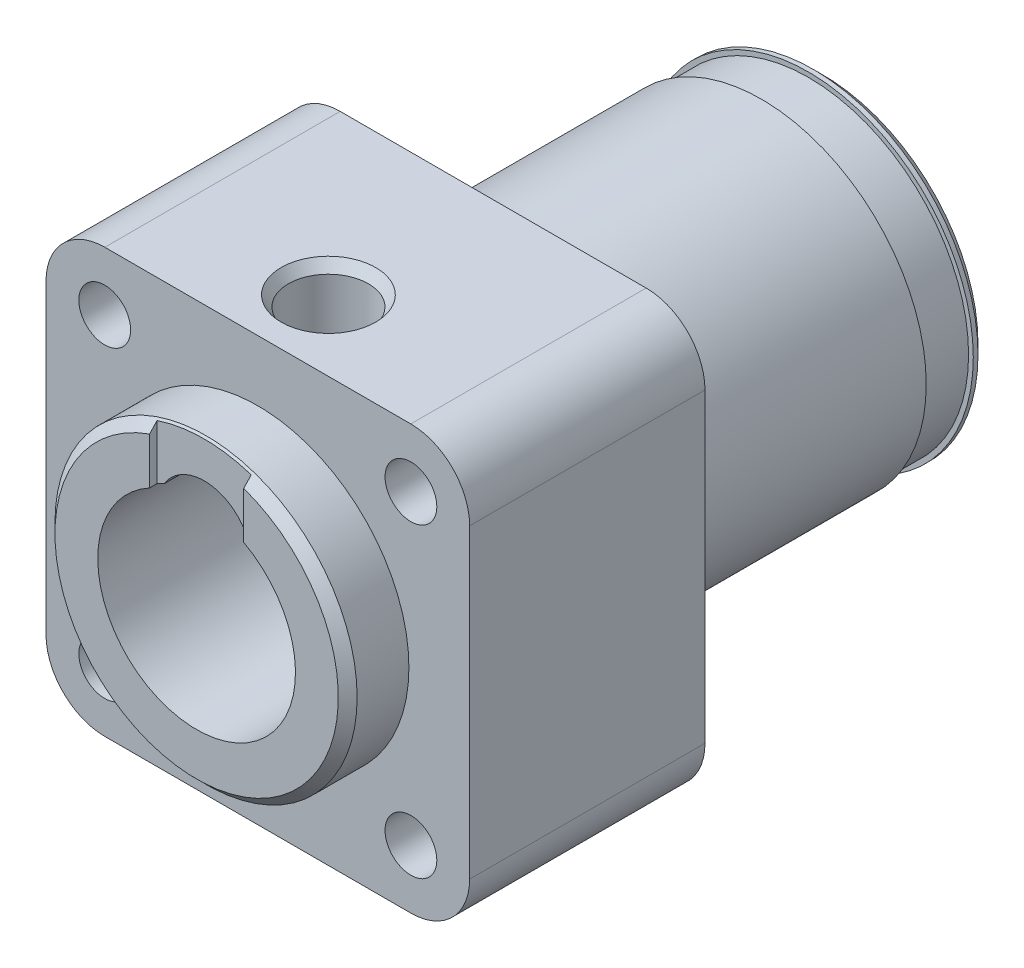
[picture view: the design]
ISO-10303-21;
HEADER;
FILE_DESCRIPTION(('STEP AP214'),'2;1');
FILE_NAME('part.step','',(''),(''),'','','');
FILE_SCHEMA(('AUTOMOTIVE_DESIGN { 1 0 10303 214 1 1 1 1 }'));
ENDSEC;
DATA;
#1=APPLICATION_CONTEXT('core data for automotive mechanical design processes');
#2=APPLICATION_PROTOCOL_DEFINITION('international standard','automotive_design',2000,#1);
#3=PRODUCT_CONTEXT('',#1,'mechanical');
#4=PRODUCT('Part','Part','',(#3));
#5=PRODUCT_RELATED_PRODUCT_CATEGORY('part','',(#4));
#6=PRODUCT_DEFINITION_FORMATION('','',#4);
#7=PRODUCT_DEFINITION_CONTEXT('part definition',#1,'design');
#8=PRODUCT_DEFINITION('design','',#6,#7);
#9=PRODUCT_DEFINITION_SHAPE('','',#8);
#10=(LENGTH_UNIT() NAMED_UNIT(*) SI_UNIT(.MILLI.,.METRE.));
#11=(NAMED_UNIT(*) PLANE_ANGLE_UNIT() SI_UNIT($,.RADIAN.));
#12=(NAMED_UNIT(*) SI_UNIT($,.STERADIAN.) SOLID_ANGLE_UNIT());
#13=UNCERTAINTY_MEASURE_WITH_UNIT(LENGTH_MEASURE(1.E-05),#10,'distance_accuracy_value','');
#14=(GEOMETRIC_REPRESENTATION_CONTEXT(3) GLOBAL_UNCERTAINTY_ASSIGNED_CONTEXT((#13)) GLOBAL_UNIT_ASSIGNED_CONTEXT((#10,
#11,#12)) REPRESENTATION_CONTEXT('',''));
#15=CARTESIAN_POINT('',(0.,0.,0.));
#16=DIRECTION('',(0.,0.,1.));
#17=DIRECTION('',(1.,0.,0.));
#18=AXIS2_PLACEMENT_3D('',#15,#16,#17);
#19=CARTESIAN_POINT('',(0.,23.75,35.));
#20=DIRECTION('',(0.,0.,1.));
#21=DIRECTION('',(1.,0.,0.));
#22=AXIS2_PLACEMENT_3D('',#19,#20,#21);
#23=PLANE('',#22);
#24=CARTESIAN_POINT('',(-16.2634559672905,16.2634559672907,35.));
#25=DIRECTION('',(0.,0.,1.));
#26=DIRECTION('',(1.,0.,0.));
#27=AXIS2_PLACEMENT_3D('',#24,#25,#26);
#28=CIRCLE('',#27,2.74999999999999);
#29=CARTESIAN_POINT('',(-13.5134559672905,16.2634559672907,35.));
#30=VERTEX_POINT('',#29);
#31=EDGE_CURVE('E373',#30,#30,#28,.T.);
#32=ORIENTED_EDGE('',*,*,#31,.T.);
#33=EDGE_LOOP('',(#32));
#34=FACE_BOUND('',#33,.T.);
#35=CARTESIAN_POINT('',(16.2634559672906,16.2634559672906,35.));
#36=DIRECTION('',(0.,0.,1.));
#37=DIRECTION('',(1.,0.,0.));
#38=AXIS2_PLACEMENT_3D('',#35,#36,#37);
#39=CIRCLE('',#38,2.74999999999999);
#40=CARTESIAN_POINT('',(19.0134559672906,16.2634559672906,35.));
#41=VERTEX_POINT('',#40);
#42=EDGE_CURVE('E367',#41,#41,#39,.T.);
#43=ORIENTED_EDGE('',*,*,#42,.T.);
#44=EDGE_LOOP('',(#43));
#45=FACE_BOUND('',#44,.T.);
#46=CARTESIAN_POINT('',(16.2634559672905,-16.2634559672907,35.));
#47=DIRECTION('',(0.,0.,1.));
#48=DIRECTION('',(1.,0.,0.));
#49=AXIS2_PLACEMENT_3D('',#46,#47,#48);
#50=CIRCLE('',#49,2.74999999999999);
#51=CARTESIAN_POINT('',(19.0134559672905,-16.2634559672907,35.));
#52=VERTEX_POINT('',#51);
#53=EDGE_CURVE('E361',#52,#52,#50,.T.);
#54=ORIENTED_EDGE('',*,*,#53,.T.);
#55=EDGE_LOOP('',(#54));
#56=FACE_BOUND('',#55,.T.);
#57=CARTESIAN_POINT('',(-16.2634559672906,-16.2634559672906,35.));
#58=DIRECTION('',(0.,0.,1.));
#59=DIRECTION('',(1.,0.,0.));
#60=AXIS2_PLACEMENT_3D('',#57,#58,#59);
#61=CIRCLE('',#60,2.74999999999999);
#62=CARTESIAN_POINT('',(-13.5134559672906,-16.2634559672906,35.));
#63=VERTEX_POINT('',#62);
#64=EDGE_CURVE('E156',#63,#63,#61,.T.);
#65=ORIENTED_EDGE('',*,*,#64,.T.);
#66=EDGE_LOOP('',(#65));
#67=FACE_BOUND('',#66,.T.);
#68=CARTESIAN_POINT('',(0.,0.,35.));
#69=DIRECTION('',(0.,0.,1.));
#70=DIRECTION('',(1.,0.,0.));
#71=AXIS2_PLACEMENT_3D('',#68,#69,#70);
#72=CIRCLE('',#71,17.5);
#73=CARTESIAN_POINT('',(17.5,0.,35.));
#74=VERTEX_POINT('',#73);
#75=EDGE_CURVE('E241',#74,#74,#72,.T.);
#76=ORIENTED_EDGE('',*,*,#75,.T.);
#77=EDGE_LOOP('',(#76));
#78=FACE_BOUND('',#77,.T.);
#79=CARTESIAN_POINT('',(-16.25,-16.25,35.));
#80=DIRECTION('',(0.,0.,1.));
#81=DIRECTION('',(1.,0.,0.));
#82=AXIS2_PLACEMENT_3D('',#79,#80,#81);
#83=CIRCLE('',#82,6.25);
#84=CARTESIAN_POINT('',(-22.5,-16.25,35.));
#85=VERTEX_POINT('',#84);
#86=CARTESIAN_POINT('',(-16.25,-22.5,35.));
#87=VERTEX_POINT('',#86);
#88=EDGE_CURVE('E270',#85,#87,#83,.T.);
#89=ORIENTED_EDGE('',*,*,#88,.F.);
#90=DIRECTION('',(0.,-1.,0.));
#91=VECTOR('',#90,1.);
#92=CARTESIAN_POINT('',(-22.5,23.75,35.));
#93=LINE('',#92,#91);
#94=CARTESIAN_POINT('',(-22.5,16.25,35.));
#95=VERTEX_POINT('',#94);
#96=EDGE_CURVE('E273',#95,#85,#93,.T.);
#97=ORIENTED_EDGE('',*,*,#96,.F.);
#98=CARTESIAN_POINT('',(-16.25,16.25,35.));
#99=DIRECTION('',(0.,0.,1.));
#100=DIRECTION('',(1.,0.,0.));
#101=AXIS2_PLACEMENT_3D('',#98,#99,#100);
#102=CIRCLE('',#101,6.25);
#103=CARTESIAN_POINT('',(-16.25,22.5,35.));
#104=VERTEX_POINT('',#103);
#105=EDGE_CURVE('E275',#104,#95,#102,.T.);
#106=ORIENTED_EDGE('',*,*,#105,.F.);
#107=DIRECTION('',(-1.,0.,0.));
#108=VECTOR('',#107,1.);
#109=CARTESIAN_POINT('',(0.,22.5,35.));
#110=LINE('',#109,#108);
#111=CARTESIAN_POINT('',(16.25,22.5,35.));
#112=VERTEX_POINT('',#111);
#113=EDGE_CURVE('E277',#112,#104,#110,.T.);
#114=ORIENTED_EDGE('',*,*,#113,.F.);
#115=CARTESIAN_POINT('',(16.25,16.25,35.));
#116=DIRECTION('',(0.,0.,1.));
#117=DIRECTION('',(1.,0.,0.));
#118=AXIS2_PLACEMENT_3D('',#115,#116,#117);
#119=CIRCLE('',#118,6.25);
#120=CARTESIAN_POINT('',(22.5,16.25,35.));
#121=VERTEX_POINT('',#120);
#122=EDGE_CURVE('E279',#121,#112,#119,.T.);
#123=ORIENTED_EDGE('',*,*,#122,.F.);
#124=DIRECTION('',(0.,1.,0.));
#125=VECTOR('',#124,1.);
#126=CARTESIAN_POINT('',(22.5,23.75,35.));
#127=LINE('',#126,#125);
#128=CARTESIAN_POINT('',(22.5,-16.25,35.));
#129=VERTEX_POINT('',#128);
#130=EDGE_CURVE('E281',#129,#121,#127,.T.);
#131=ORIENTED_EDGE('',*,*,#130,.F.);
#132=CARTESIAN_POINT('',(16.25,-16.25,35.));
#133=DIRECTION('',(0.,0.,1.));
#134=DIRECTION('',(1.,0.,0.));
#135=AXIS2_PLACEMENT_3D('',#132,#133,#134);
#136=CIRCLE('',#135,6.25);
#137=CARTESIAN_POINT('',(16.25,-22.5,35.));
#138=VERTEX_POINT('',#137);
#139=EDGE_CURVE('E283',#138,#129,#136,.T.);
#140=ORIENTED_EDGE('',*,*,#139,.F.);
#141=DIRECTION('',(1.,0.,0.));
#142=VECTOR('',#141,1.);
#143=CARTESIAN_POINT('',(0.,-22.5,35.));
#144=LINE('',#143,#142);
#145=EDGE_CURVE('E285',#87,#138,#144,.T.);
#146=ORIENTED_EDGE('',*,*,#145,.F.);
#147=EDGE_LOOP('',(#89,#97,#106,#114,#123,#131,#140,#146));
#148=FACE_BOUND('',#147,.T.);
#149=ADVANCED_FACE('F30',(#34,#45,#56,#67,#78,#148),#23,.F.);
#150=CARTESIAN_POINT('',(0.,0.,60.));
#151=DIRECTION('',(0.,0.,1.));
#152=DIRECTION('',(1.,0.,0.));
#153=AXIS2_PLACEMENT_3D('',#150,#151,#152);
#154=PLANE('',#153);
#155=CARTESIAN_POINT('',(-16.2634559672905,16.2634559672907,60.));
#156=DIRECTION('',(0.,0.,1.));
#157=DIRECTION('',(1.,0.,0.));
#158=AXIS2_PLACEMENT_3D('',#155,#156,#157);
#159=CIRCLE('',#158,2.74999999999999);
#160=CARTESIAN_POINT('',(-13.5134559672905,16.2634559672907,60.));
#161=VERTEX_POINT('',#160);
#162=EDGE_CURVE('E375',#161,#161,#159,.T.);
#163=ORIENTED_EDGE('',*,*,#162,.F.);
#164=EDGE_LOOP('',(#163));
#165=FACE_BOUND('',#164,.T.);
#166=CARTESIAN_POINT('',(16.2634559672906,16.2634559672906,60.));
#167=DIRECTION('',(0.,0.,1.));
#168=DIRECTION('',(1.,0.,0.));
#169=AXIS2_PLACEMENT_3D('',#166,#167,#168);
#170=CIRCLE('',#169,2.74999999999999);
#171=CARTESIAN_POINT('',(19.0134559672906,16.2634559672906,60.));
#172=VERTEX_POINT('',#171);
#173=EDGE_CURVE('E370',#172,#172,#170,.T.);
#174=ORIENTED_EDGE('',*,*,#173,.F.);
#175=EDGE_LOOP('',(#174));
#176=FACE_BOUND('',#175,.T.);
#177=CARTESIAN_POINT('',(16.2634559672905,-16.2634559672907,60.));
#178=DIRECTION('',(0.,0.,1.));
#179=DIRECTION('',(1.,0.,0.));
#180=AXIS2_PLACEMENT_3D('',#177,#178,#179);
#181=CIRCLE('',#180,2.74999999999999);
#182=CARTESIAN_POINT('',(19.0134559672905,-16.2634559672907,60.));
#183=VERTEX_POINT('',#182);
#184=EDGE_CURVE('E364',#183,#183,#181,.T.);
#185=ORIENTED_EDGE('',*,*,#184,.F.);
#186=EDGE_LOOP('',(#185));
#187=FACE_BOUND('',#186,.T.);
#188=CARTESIAN_POINT('',(-16.2634559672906,-16.2634559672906,60.));
#189=DIRECTION('',(0.,0.,1.));
#190=DIRECTION('',(1.,0.,0.));
#191=AXIS2_PLACEMENT_3D('',#188,#189,#190);
#192=CIRCLE('',#191,2.74999999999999);
#193=CARTESIAN_POINT('',(-13.5134559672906,-16.2634559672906,60.));
#194=VERTEX_POINT('',#193);
#195=EDGE_CURVE('E358',#194,#194,#192,.T.);
#196=ORIENTED_EDGE('',*,*,#195,.F.);
#197=EDGE_LOOP('',(#196));
#198=FACE_BOUND('',#197,.T.);
#199=CARTESIAN_POINT('',(0.,0.,60.));
#200=DIRECTION('',(0.,0.,1.));
#201=DIRECTION('',(1.,0.,0.));
#202=AXIS2_PLACEMENT_3D('',#199,#200,#201);
#203=CIRCLE('',#202,16.05);
#204=CARTESIAN_POINT('',(16.05,0.,60.));
#205=VERTEX_POINT('',#204);
#206=EDGE_CURVE('E265',#205,#205,#203,.T.);
#207=ORIENTED_EDGE('',*,*,#206,.F.);
#208=EDGE_LOOP('',(#207));
#209=FACE_BOUND('',#208,.T.);
#210=DIRECTION('',(0.,-1.,0.));
#211=VECTOR('',#210,1.);
#212=CARTESIAN_POINT('',(-22.5,16.25,60.));
#213=LINE('',#212,#211);
#214=CARTESIAN_POINT('',(-22.5,16.25,60.));
#215=VERTEX_POINT('',#214);
#216=CARTESIAN_POINT('',(-22.5,-16.25,60.));
#217=VERTEX_POINT('',#216);
#218=EDGE_CURVE('E291',#215,#217,#213,.T.);
#219=ORIENTED_EDGE('',*,*,#218,.T.);
#220=CARTESIAN_POINT('',(-16.25,-16.25,60.));
#221=DIRECTION('',(0.,0.,1.));
#222=DIRECTION('',(1.,0.,0.));
#223=AXIS2_PLACEMENT_3D('',#220,#221,#222);
#224=CIRCLE('',#223,6.25);
#225=CARTESIAN_POINT('',(-16.25,-22.5,60.));
#226=VERTEX_POINT('',#225);
#227=EDGE_CURVE('E325',#217,#226,#224,.T.);
#228=ORIENTED_EDGE('',*,*,#227,.T.);
#229=DIRECTION('',(1.,0.,0.));
#230=VECTOR('',#229,1.);
#231=CARTESIAN_POINT('',(-16.25,-22.5,60.));
#232=LINE('',#231,#230);
#233=CARTESIAN_POINT('',(16.25,-22.5,60.));
#234=VERTEX_POINT('',#233);
#235=EDGE_CURVE('E322',#226,#234,#232,.T.);
#236=ORIENTED_EDGE('',*,*,#235,.T.);
#237=CARTESIAN_POINT('',(16.25,-16.25,60.));
#238=DIRECTION('',(0.,0.,1.));
#239=DIRECTION('',(1.,0.,0.));
#240=AXIS2_PLACEMENT_3D('',#237,#238,#239);
#241=CIRCLE('',#240,6.25);
#242=CARTESIAN_POINT('',(22.5,-16.25,60.));
#243=VERTEX_POINT('',#242);
#244=EDGE_CURVE('E319',#234,#243,#241,.T.);
#245=ORIENTED_EDGE('',*,*,#244,.T.);
#246=DIRECTION('',(0.,1.,0.));
#247=VECTOR('',#246,1.);
#248=CARTESIAN_POINT('',(22.5,16.25,60.));
#249=LINE('',#248,#247);
#250=CARTESIAN_POINT('',(22.5,16.25,60.));
#251=VERTEX_POINT('',#250);
#252=EDGE_CURVE('E316',#243,#251,#249,.T.);
#253=ORIENTED_EDGE('',*,*,#252,.T.);
#254=CARTESIAN_POINT('',(16.25,16.25,60.));
#255=DIRECTION('',(0.,0.,1.));
#256=DIRECTION('',(1.,0.,0.));
#257=AXIS2_PLACEMENT_3D('',#254,#255,#256);
#258=CIRCLE('',#257,6.25);
#259=CARTESIAN_POINT('',(16.25,22.5,60.));
#260=VERTEX_POINT('',#259);
#261=EDGE_CURVE('E313',#251,#260,#258,.T.);
#262=ORIENTED_EDGE('',*,*,#261,.T.);
#263=DIRECTION('',(-1.,0.,0.));
#264=VECTOR('',#263,1.);
#265=CARTESIAN_POINT('',(-16.25,22.5,60.));
#266=LINE('',#265,#264);
#267=CARTESIAN_POINT('',(-16.25,22.5,60.));
#268=VERTEX_POINT('',#267);
#269=EDGE_CURVE('E310',#260,#268,#266,.T.);
#270=ORIENTED_EDGE('',*,*,#269,.T.);
#271=CARTESIAN_POINT('',(-16.25,16.25,60.));
#272=DIRECTION('',(0.,0.,1.));
#273=DIRECTION('',(1.,0.,0.));
#274=AXIS2_PLACEMENT_3D('',#271,#272,#273);
#275=CIRCLE('',#274,6.25);
#276=EDGE_CURVE('E307',#268,#215,#275,.T.);
#277=ORIENTED_EDGE('',*,*,#276,.T.);
#278=EDGE_LOOP('',(#219,#228,#236,#245,#253,#262,#270,#277));
#279=FACE_BOUND('',#278,.T.);
#280=ADVANCED_FACE('F201',(#165,#176,#187,#198,#209,#279),#154,.T.);
#281=CARTESIAN_POINT('',(0.,0.,66.5));
#282=DIRECTION('',(0.,0.,1.));
#283=DIRECTION('',(1.,0.,0.));
#284=AXIS2_PLACEMENT_3D('',#281,#282,#283);
#285=PLANE('',#284);
#286=DIRECTION('',(0.,-1.,0.));
#287=VECTOR('',#286,1.);
#288=CARTESIAN_POINT('',(-5.,0.,66.5));
#289=LINE('',#288,#287);
#290=CARTESIAN_POINT('',(-5.,14.1951576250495,66.5));
#291=VERTEX_POINT('',#290);
#292=CARTESIAN_POINT('',(-5.,9.23309265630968,66.5));
#293=VERTEX_POINT('',#292);
#294=EDGE_CURVE('E141',#291,#293,#289,.T.);
#295=ORIENTED_EDGE('',*,*,#294,.F.);
#296=CARTESIAN_POINT('',(0.,0.,66.5));
#297=DIRECTION('',(0.,0.,1.));
#298=DIRECTION('',(1.,0.,0.));
#299=AXIS2_PLACEMENT_3D('',#296,#297,#298);
#300=CIRCLE('',#299,15.05);
#301=CARTESIAN_POINT('',(5.,14.1951576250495,66.5));
#302=VERTEX_POINT('',#301);
#303=EDGE_CURVE('E152',#291,#302,#300,.T.);
#304=ORIENTED_EDGE('',*,*,#303,.T.);
#305=DIRECTION('',(0.,1.,0.));
#306=VECTOR('',#305,1.);
#307=CARTESIAN_POINT('',(5.,0.,66.5));
#308=LINE('',#307,#306);
#309=CARTESIAN_POINT('',(5.,9.23309265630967,66.5));
#310=VERTEX_POINT('',#309);
#311=EDGE_CURVE('E155',#310,#302,#308,.T.);
#312=ORIENTED_EDGE('',*,*,#311,.F.);
#313=CARTESIAN_POINT('',(0.,0.,66.5));
#314=DIRECTION('',(0.,0.,-1.));
#315=DIRECTION('',(-1.,0.,0.));
#316=AXIS2_PLACEMENT_3D('',#313,#314,#315);
#317=CIRCLE('',#316,10.5);
#318=EDGE_CURVE('E154',#310,#293,#317,.T.);
#319=ORIENTED_EDGE('',*,*,#318,.T.);
#320=EDGE_LOOP('',(#295,#304,#312,#319));
#321=FACE_BOUND('',#320,.T.);
#322=ADVANCED_FACE('F150',(#321),#285,.T.);
#323=CARTESIAN_POINT('',(0.,0.,0.));
#324=DIRECTION('',(0.,0.,-1.));
#325=DIRECTION('',(-1.,0.,0.));
#326=AXIS2_PLACEMENT_3D('',#323,#324,#325);
#327=CYLINDRICAL_SURFACE('',#326,10.5);
#328=ORIENTED_EDGE('',*,*,#318,.F.);
#329=DIRECTION('',(0.,0.,-1.));
#330=VECTOR('',#329,1.);
#331=CARTESIAN_POINT('',(5.,9.23309265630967,0.));
#332=LINE('',#331,#330);
#333=CARTESIAN_POINT('',(5.,9.23309265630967,65.7));
#334=VERTEX_POINT('',#333);
#335=EDGE_CURVE('E344',#310,#334,#332,.T.);
#336=ORIENTED_EDGE('',*,*,#335,.T.);
#337=CARTESIAN_POINT('',(0.,0.,65.7));
#338=DIRECTION('',(0.,0.,-1.));
#339=DIRECTION('',(-1.,0.,0.));
#340=AXIS2_PLACEMENT_3D('',#337,#338,#339);
#341=CIRCLE('',#340,10.5);
#342=CARTESIAN_POINT('',(4.30463640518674,9.57706141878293,65.7));
#343=VERTEX_POINT('',#342);
#344=EDGE_CURVE('E349',#334,#343,#341,.F.);
#345=ORIENTED_EDGE('',*,*,#344,.T.);
#346=DIRECTION('',(0.,0.,1.));
#347=VECTOR('',#346,1.);
#348=CARTESIAN_POINT('',(4.30463640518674,9.57706141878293,46.5));
#349=LINE('',#348,#347);
#350=CARTESIAN_POINT('',(4.30463640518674,9.57706141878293,46.5));
#351=VERTEX_POINT('',#350);
#352=EDGE_CURVE('E334',#351,#343,#349,.T.);
#353=ORIENTED_EDGE('',*,*,#352,.F.);
#354=CARTESIAN_POINT('',(0.,0.,46.5));
#355=DIRECTION('',(0.,0.,-1.));
#356=DIRECTION('',(-1.,0.,0.));
#357=AXIS2_PLACEMENT_3D('',#354,#355,#356);
#358=CIRCLE('',#357,10.5);
#359=CARTESIAN_POINT('',(-4.24999999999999,9.60143218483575,46.5));
#360=VERTEX_POINT('',#359);
#361=EDGE_CURVE('E177',#351,#360,#358,.F.);
#362=ORIENTED_EDGE('',*,*,#361,.T.);
#363=DIRECTION('',(0.,0.,1.));
#364=VECTOR('',#363,1.);
#365=CARTESIAN_POINT('',(-4.24999999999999,9.60143218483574,46.5));
#366=LINE('',#365,#364);
#367=CARTESIAN_POINT('',(-4.24999999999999,9.60143218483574,52.5));
#368=VERTEX_POINT('',#367);
#369=EDGE_CURVE('E335',#360,#368,#366,.T.);
#370=ORIENTED_EDGE('',*,*,#369,.T.);
#371=CARTESIAN_POINT('',(-4.24999999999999,9.60143218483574,65.7));
#372=VERTEX_POINT('',#371);
#373=EDGE_CURVE('E338',#368,#372,#366,.T.);
#374=ORIENTED_EDGE('',*,*,#373,.T.);
#375=CARTESIAN_POINT('',(-5.,9.23309265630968,65.7));
#376=VERTEX_POINT('',#375);
#377=EDGE_CURVE('E50',#372,#376,#341,.F.);
#378=ORIENTED_EDGE('',*,*,#377,.T.);
#379=DIRECTION('',(0.,0.,-1.));
#380=VECTOR('',#379,1.);
#381=CARTESIAN_POINT('',(-5.,9.23309265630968,0.));
#382=LINE('',#381,#380);
#383=EDGE_CURVE('E342',#376,#293,#382,.F.);
#384=ORIENTED_EDGE('',*,*,#383,.T.);
#385=EDGE_LOOP('',(#328,#336,#345,#353,#362,#370,#374,#378,#384));
#386=FACE_BOUND('',#385,.T.);
#387=CARTESIAN_POINT('',(0.,0.,32.));
#388=DIRECTION('',(0.,0.,-1.));
#389=DIRECTION('',(-1.,0.,0.));
#390=AXIS2_PLACEMENT_3D('',#387,#388,#389);
#391=CIRCLE('',#390,10.5);
#392=CARTESIAN_POINT('',(-10.5,0.,32.));
#393=VERTEX_POINT('',#392);
#394=EDGE_CURVE('E246',#393,#393,#391,.F.);
#395=ORIENTED_EDGE('',*,*,#394,.F.);
#396=EDGE_LOOP('',(#395));
#397=FACE_BOUND('',#396,.T.);
#398=ADVANCED_FACE('F217',(#386,#397),#327,.F.);
#399=CARTESIAN_POINT('',(0.,0.,66.5));
#400=DIRECTION('',(0.,0.,1.));
#401=DIRECTION('',(1.,0.,0.));
#402=AXIS2_PLACEMENT_3D('',#399,#400,#401);
#403=CYLINDRICAL_SURFACE('',#402,17.5);
#404=ORIENTED_EDGE('',*,*,#75,.F.);
#405=EDGE_LOOP('',(#404));
#406=FACE_BOUND('',#405,.T.);
#407=CARTESIAN_POINT('',(0.,0.,6.50000000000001));
#408=DIRECTION('',(0.,0.,1.));
#409=DIRECTION('',(1.,0.,0.));
#410=AXIS2_PLACEMENT_3D('',#407,#408,#409);
#411=CIRCLE('',#410,17.5);
#412=CARTESIAN_POINT('',(17.5,0.,6.50000000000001));
#413=VERTEX_POINT('',#412);
#414=EDGE_CURVE('E243',#413,#413,#411,.T.);
#415=ORIENTED_EDGE('',*,*,#414,.T.);
#416=EDGE_LOOP('',(#415));
#417=FACE_BOUND('',#416,.T.);
#418=ADVANCED_FACE('F452',(#406,#417),#403,.T.);
#419=CARTESIAN_POINT('',(0.,23.75,6.5));
#420=DIRECTION('',(0.,0.,-1.));
#421=DIRECTION('',(-1.,0.,0.));
#422=AXIS2_PLACEMENT_3D('',#419,#420,#421);
#423=PLANE('',#422);
#424=CARTESIAN_POINT('',(0.,0.,6.5));
#425=DIRECTION('',(0.,0.,1.));
#426=DIRECTION('',(1.,0.,0.));
#427=AXIS2_PLACEMENT_3D('',#424,#425,#426);
#428=CIRCLE('',#427,17.);
#429=CARTESIAN_POINT('',(17.,0.,6.5));
#430=VERTEX_POINT('',#429);
#431=EDGE_CURVE('E252',#430,#430,#428,.T.);
#432=ORIENTED_EDGE('',*,*,#431,.T.);
#433=EDGE_LOOP('',(#432));
#434=FACE_BOUND('',#433,.T.);
#435=ORIENTED_EDGE('',*,*,#414,.F.);
#436=EDGE_LOOP('',(#435));
#437=FACE_BOUND('',#436,.T.);
#438=ADVANCED_FACE('F213',(#434,#437),#423,.T.);
#439=CARTESIAN_POINT('',(0.,0.,66.5));
#440=DIRECTION('',(0.,0.,1.));
#441=DIRECTION('',(1.,0.,0.));
#442=AXIS2_PLACEMENT_3D('',#439,#440,#441);
#443=CYLINDRICAL_SURFACE('',#442,17.);
#444=CARTESIAN_POINT('',(0.,0.,1.5));
#445=DIRECTION('',(0.,0.,1.));
#446=DIRECTION('',(1.,0.,0.));
#447=AXIS2_PLACEMENT_3D('',#444,#445,#446);
#448=CIRCLE('',#447,17.);
#449=CARTESIAN_POINT('',(17.,0.,1.5));
#450=VERTEX_POINT('',#449);
#451=EDGE_CURVE('E255',#450,#450,#448,.T.);
#452=ORIENTED_EDGE('',*,*,#451,.T.);
#453=EDGE_LOOP('',(#452));
#454=FACE_BOUND('',#453,.T.);
#455=ORIENTED_EDGE('',*,*,#431,.F.);
#456=EDGE_LOOP('',(#455));
#457=FACE_BOUND('',#456,.T.);
#458=ADVANCED_FACE('F458',(#454,#457),#443,.T.);
#459=CARTESIAN_POINT('',(0.,23.75,1.5));
#460=DIRECTION('',(0.,0.,1.));
#461=DIRECTION('',(1.,0.,0.));
#462=AXIS2_PLACEMENT_3D('',#459,#460,#461);
#463=PLANE('',#462);
#464=CARTESIAN_POINT('',(0.,0.,1.5));
#465=DIRECTION('',(0.,0.,1.));
#466=DIRECTION('',(1.,0.,0.));
#467=AXIS2_PLACEMENT_3D('',#464,#465,#466);
#468=CIRCLE('',#467,17.5);
#469=CARTESIAN_POINT('',(17.5,0.,1.5));
#470=VERTEX_POINT('',#469);
#471=EDGE_CURVE('E258',#470,#470,#468,.T.);
#472=ORIENTED_EDGE('',*,*,#471,.T.);
#473=EDGE_LOOP('',(#472));
#474=FACE_BOUND('',#473,.T.);
#475=ORIENTED_EDGE('',*,*,#451,.F.);
#476=EDGE_LOOP('',(#475));
#477=FACE_BOUND('',#476,.T.);
#478=ADVANCED_FACE('F456',(#474,#477),#463,.T.);
#479=CARTESIAN_POINT('',(0.,0.,1.00000000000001));
#480=DIRECTION('',(0.,0.,1.));
#481=DIRECTION('',(1.,0.,0.));
#482=AXIS2_PLACEMENT_3D('',#479,#480,#481);
#483=CIRCLE('',#482,17.5);
#484=CARTESIAN_POINT('',(17.5,0.,1.00000000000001));
#485=VERTEX_POINT('',#484);
#486=EDGE_CURVE('E167',#485,#485,#483,.T.);
#487=ORIENTED_EDGE('',*,*,#486,.T.);
#488=EDGE_LOOP('',(#487));
#489=FACE_BOUND('',#488,.T.);
#490=ORIENTED_EDGE('',*,*,#471,.F.);
#491=EDGE_LOOP('',(#490));
#492=FACE_BOUND('',#491,.T.);
#493=ADVANCED_FACE('F221',(#489,#492),#403,.T.);
#494=CARTESIAN_POINT('',(0.,0.,0.));
#495=DIRECTION('',(0.,0.,1.));
#496=DIRECTION('',(1.,0.,0.));
#497=AXIS2_PLACEMENT_3D('',#494,#495,#496);
#498=PLANE('',#497);
#499=CARTESIAN_POINT('',(0.,0.,0.));
#500=DIRECTION('',(0.,0.,1.));
#501=DIRECTION('',(1.,0.,0.));
#502=AXIS2_PLACEMENT_3D('',#499,#500,#501);
#503=CIRCLE('',#502,16.5);
#504=CARTESIAN_POINT('',(16.5,0.,0.));
#505=VERTEX_POINT('',#504);
#506=EDGE_CURVE('E161',#505,#505,#503,.F.);
#507=ORIENTED_EDGE('',*,*,#506,.T.);
#508=EDGE_LOOP('',(#507));
#509=FACE_BOUND('',#508,.T.);
#510=CARTESIAN_POINT('',(0.,0.,0.));
#511=DIRECTION('',(0.,0.,-1.));
#512=DIRECTION('',(-1.,0.,0.));
#513=AXIS2_PLACEMENT_3D('',#510,#511,#512);
#514=CIRCLE('',#513,14.5);
#515=CARTESIAN_POINT('',(-14.5,0.,0.));
#516=VERTEX_POINT('',#515);
#517=EDGE_CURVE('E262',#516,#516,#514,.T.);
#518=ORIENTED_EDGE('',*,*,#517,.F.);
#519=EDGE_LOOP('',(#518));
#520=FACE_BOUND('',#519,.T.);
#521=ADVANCED_FACE('F218',(#509,#520),#498,.F.);
#522=CARTESIAN_POINT('',(0.,0.,32.));
#523=DIRECTION('',(0.,0.,-1.));
#524=DIRECTION('',(-1.,0.,0.));
#525=AXIS2_PLACEMENT_3D('',#522,#523,#524);
#526=PLANE('',#525);
#527=CARTESIAN_POINT('',(0.,0.,32.));
#528=DIRECTION('',(0.,0.,-1.));
#529=DIRECTION('',(-1.,0.,0.));
#530=AXIS2_PLACEMENT_3D('',#527,#528,#529);
#531=CIRCLE('',#530,14.5);
#532=CARTESIAN_POINT('',(-14.5,0.,32.));
#533=VERTEX_POINT('',#532);
#534=EDGE_CURVE('E248',#533,#533,#531,.T.);
#535=ORIENTED_EDGE('',*,*,#534,.T.);
#536=EDGE_LOOP('',(#535));
#537=FACE_BOUND('',#536,.T.);
#538=ORIENTED_EDGE('',*,*,#394,.T.);
#539=EDGE_LOOP('',(#538));
#540=FACE_BOUND('',#539,.T.);
#541=ADVANCED_FACE('F220',(#537,#540),#526,.T.);
#542=CARTESIAN_POINT('',(0.,0.,32.));
#543=DIRECTION('',(0.,0.,-1.));
#544=DIRECTION('',(-1.,0.,0.));
#545=AXIS2_PLACEMENT_3D('',#542,#543,#544);
#546=CYLINDRICAL_SURFACE('',#545,14.5);
#547=ORIENTED_EDGE('',*,*,#534,.F.);
#548=EDGE_LOOP('',(#547));
#549=FACE_BOUND('',#548,.T.);
#550=ORIENTED_EDGE('',*,*,#517,.T.);
#551=EDGE_LOOP('',(#550));
#552=FACE_BOUND('',#551,.T.);
#553=ADVANCED_FACE('F226',(#549,#552),#546,.F.);
#554=CARTESIAN_POINT('',(0.,0.,1.00000000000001));
#555=DIRECTION('',(0.,0.,1.));
#556=DIRECTION('',(1.,0.,0.));
#557=AXIS2_PLACEMENT_3D('',#554,#555,#556);
#558=CONICAL_SURFACE('',#557,17.5,0.785398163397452);
#559=ORIENTED_EDGE('',*,*,#506,.F.);
#560=EDGE_LOOP('',(#559));
#561=FACE_BOUND('',#560,.T.);
#562=ORIENTED_EDGE('',*,*,#486,.F.);
#563=EDGE_LOOP('',(#562));
#564=FACE_BOUND('',#563,.T.);
#565=ADVANCED_FACE('F223',(#561,#564),#558,.T.);
#566=CARTESIAN_POINT('',(0.,0.,60.));
#567=DIRECTION('',(0.,0.,1.));
#568=DIRECTION('',(1.,0.,0.));
#569=AXIS2_PLACEMENT_3D('',#566,#567,#568);
#570=CYLINDRICAL_SURFACE('',#569,16.05);
#571=CARTESIAN_POINT('',(0.,0.,65.5));
#572=DIRECTION('',(0.,0.,1.));
#573=DIRECTION('',(1.,0.,0.));
#574=AXIS2_PLACEMENT_3D('',#571,#572,#573);
#575=CIRCLE('',#574,16.05);
#576=CARTESIAN_POINT('',(16.05,0.,65.5));
#577=VERTEX_POINT('',#576);
#578=EDGE_CURVE('E160',#577,#577,#575,.F.);
#579=CARTESIAN_POINT('',(16.05,0.,65.5));
#580=CARTESIAN_POINT('',(16.05,0.,65.4427083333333));
#581=CARTESIAN_POINT('',(16.05,0.,65.3854166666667));
#582=CARTESIAN_POINT('',(16.05,0.,65.2708333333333));
#583=CARTESIAN_POINT('',(16.05,0.,65.2135416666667));
#584=CARTESIAN_POINT('',(16.05,0.,65.0989583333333));
#585=CARTESIAN_POINT('',(16.05,0.,65.0416666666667));
#586=CARTESIAN_POINT('',(16.05,0.,64.9270833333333));
#587=CARTESIAN_POINT('',(16.05,0.,64.8697916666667));
#588=CARTESIAN_POINT('',(16.05,0.,64.7552083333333));
#589=CARTESIAN_POINT('',(16.05,0.,64.6979166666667));
#590=CARTESIAN_POINT('',(16.05,0.,64.5833333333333));
#591=CARTESIAN_POINT('',(16.05,0.,64.5260416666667));
#592=CARTESIAN_POINT('',(16.05,0.,64.4114583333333));
#593=CARTESIAN_POINT('',(16.05,0.,64.3541666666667));
#594=CARTESIAN_POINT('',(16.05,0.,64.2395833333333));
#595=CARTESIAN_POINT('',(16.05,0.,64.1822916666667));
#596=CARTESIAN_POINT('',(16.05,0.,64.0677083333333));
#597=CARTESIAN_POINT('',(16.05,0.,64.0104166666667));
#598=CARTESIAN_POINT('',(16.05,0.,63.8958333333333));
#599=CARTESIAN_POINT('',(16.05,0.,63.8385416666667));
#600=CARTESIAN_POINT('',(16.05,0.,63.7239583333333));
#601=CARTESIAN_POINT('',(16.05,0.,63.6666666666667));
#602=CARTESIAN_POINT('',(16.05,0.,63.5520833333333));
#603=CARTESIAN_POINT('',(16.05,0.,63.4947916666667));
#604=CARTESIAN_POINT('',(16.05,0.,63.3802083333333));
#605=CARTESIAN_POINT('',(16.05,0.,63.3229166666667));
#606=CARTESIAN_POINT('',(16.05,0.,63.2083333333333));
#607=CARTESIAN_POINT('',(16.05,0.,63.1510416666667));
#608=CARTESIAN_POINT('',(16.05,0.,63.0364583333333));
#609=CARTESIAN_POINT('',(16.05,0.,62.9791666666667));
#610=CARTESIAN_POINT('',(16.05,0.,62.8645833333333));
#611=CARTESIAN_POINT('',(16.05,0.,62.8072916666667));
#612=CARTESIAN_POINT('',(16.05,0.,62.6927083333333));
#613=CARTESIAN_POINT('',(16.05,0.,62.6354166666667));
#614=CARTESIAN_POINT('',(16.05,0.,62.5208333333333));
#615=CARTESIAN_POINT('',(16.05,0.,62.4635416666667));
#616=CARTESIAN_POINT('',(16.05,0.,62.3489583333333));
#617=CARTESIAN_POINT('',(16.05,0.,62.2916666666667));
#618=CARTESIAN_POINT('',(16.05,0.,62.1770833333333));
#619=CARTESIAN_POINT('',(16.05,0.,62.1197916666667));
#620=CARTESIAN_POINT('',(16.05,0.,62.0052083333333));
#621=CARTESIAN_POINT('',(16.05,0.,61.9479166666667));
#622=CARTESIAN_POINT('',(16.05,0.,61.8333333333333));
#623=CARTESIAN_POINT('',(16.05,0.,61.7760416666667));
#624=CARTESIAN_POINT('',(16.05,0.,61.6614583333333));
#625=CARTESIAN_POINT('',(16.05,0.,61.6041666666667));
#626=CARTESIAN_POINT('',(16.05,0.,61.4895833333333));
#627=CARTESIAN_POINT('',(16.05,0.,61.4322916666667));
#628=CARTESIAN_POINT('',(16.05,0.,61.3177083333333));
#629=CARTESIAN_POINT('',(16.05,0.,61.2604166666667));
#630=CARTESIAN_POINT('',(16.05,0.,61.1458333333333));
#631=CARTESIAN_POINT('',(16.05,0.,61.0885416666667));
#632=CARTESIAN_POINT('',(16.05,0.,60.9739583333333));
#633=CARTESIAN_POINT('',(16.05,0.,60.9166666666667));
#634=CARTESIAN_POINT('',(16.05,0.,60.8020833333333));
#635=CARTESIAN_POINT('',(16.05,0.,60.7447916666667));
#636=CARTESIAN_POINT('',(16.05,0.,60.6302083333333));
#637=CARTESIAN_POINT('',(16.05,0.,60.5729166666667));
#638=CARTESIAN_POINT('',(16.05,0.,60.4583333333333));
#639=CARTESIAN_POINT('',(16.05,0.,60.4010416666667));
#640=CARTESIAN_POINT('',(16.05,0.,60.2864583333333));
#641=CARTESIAN_POINT('',(16.05,0.,60.2291666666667));
#642=CARTESIAN_POINT('',(16.05,0.,60.1145833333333));
#643=CARTESIAN_POINT('',(16.05,0.,60.0572916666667));
#644=CARTESIAN_POINT('',(16.05,0.,60.));
#645=B_SPLINE_CURVE_WITH_KNOTS('',3,(#579,#580,#581,#582,#583,#584,#585,#586,#587,#588,#589,
#590,#591,#592,#593,#594,#595,#596,#597,#598,#599,#600,#601,#602,#603,#604,#605,#606,#607,#608,
#609,#610,#611,#612,#613,#614,#615,#616,#617,#618,#619,#620,#621,#622,#623,#624,#625,#626,#627,
#628,#629,#630,#631,#632,#633,#634,#635,#636,#637,#638,#639,#640,#641,#642,#643,#644),
.UNSPECIFIED.,.F.,.F.,(4,2,2,2,2,2,2,2,2,2,2,2,2,2,2,2,2,2,2,2,2,2,2,2,2,2,2,2,2,2,2,2,4),(0.,
0.171874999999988,0.34374999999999,0.515624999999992,0.687499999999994,0.859374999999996,
1.03125,1.203125,1.37499999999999,1.54687499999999,1.71874999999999,1.89062499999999,
2.06249999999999,2.234375,2.40624999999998,2.57812499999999,2.74999999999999,2.92187499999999,
3.09374999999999,3.26562499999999,3.43749999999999,3.60937499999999,3.78124999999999,
3.95312499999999,4.12499999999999,4.29687499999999,4.46874999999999,4.64062499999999,
4.81249999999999,4.98437499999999,5.15624999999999,5.32812499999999,5.49999999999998),.UNSPECIFIED.);
#646=EDGE_CURVE('BSEAM225',#577,#205,#645,.T.);
#647=ORIENTED_EDGE('',*,*,#578,.T.);
#648=ORIENTED_EDGE('',*,*,#206,.T.);
#649=ORIENTED_EDGE('',*,*,#646,.T.);
#650=ORIENTED_EDGE('',*,*,#646,.F.);
#651=EDGE_LOOP('',(#647,#649,#648,#650));
#652=FACE_BOUND('',#651,.T.);
#653=ADVANCED_FACE('F225',(#652),#570,.T.);
#654=CARTESIAN_POINT('',(0.,0.,66.5));
#655=DIRECTION('',(0.,0.,-1.));
#656=DIRECTION('',(-1.,0.,0.));
#657=AXIS2_PLACEMENT_3D('',#654,#655,#656);
#658=CONICAL_SURFACE('',#657,15.05,0.785398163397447);
#659=CARTESIAN_POINT('',(-5.,27.070309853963,54.0218021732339));
#660=CARTESIAN_POINT('',(-5.,26.5424236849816,54.5408982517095));
#661=CARTESIAN_POINT('',(-5.,26.0142960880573,55.0597491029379));
#662=CARTESIAN_POINT('',(-5.,24.9574402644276,56.0968402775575));
#663=CARTESIAN_POINT('',(-5.,24.4287120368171,56.6150806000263));
#664=CARTESIAN_POINT('',(-5.,23.3705205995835,57.6508468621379));
#665=CARTESIAN_POINT('',(-5.,22.8410573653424,58.1683727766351));
#666=CARTESIAN_POINT('',(-5.,21.7812543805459,59.2025259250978));
#667=CARTESIAN_POINT('',(-5.,21.2509146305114,59.7191531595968));
#668=CARTESIAN_POINT('',(-5.,20.1893306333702,60.7511162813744));
#669=CARTESIAN_POINT('',(-5.,19.6580867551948,61.2664525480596));
#670=CARTESIAN_POINT('',(-5.,18.594235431,62.2957155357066));
#671=CARTESIAN_POINT('',(-5.,18.0616279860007,62.8096422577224));
#672=CARTESIAN_POINT('',(-5.,16.9946664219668,63.8356765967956));
#673=CARTESIAN_POINT('',(-5.,16.4603123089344,64.3477842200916));
#674=CARTESIAN_POINT('',(-5.,15.3893173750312,65.3696018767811));
#675=CARTESIAN_POINT('',(-5.,14.852676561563,65.8793119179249));
#676=CARTESIAN_POINT('',(-5.,13.8464597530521,66.8292438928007));
#677=CARTESIAN_POINT('',(-5.,13.3772594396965,67.2698635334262));
#678=CARTESIAN_POINT('',(-5.,12.4357769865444,68.1477801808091));
#679=CARTESIAN_POINT('',(-5.,11.9634949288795,68.5850772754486));
#680=CARTESIAN_POINT('',(-5.,11.2518562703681,69.2375924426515));
#681=CARTESIAN_POINT('',(-5.,11.0140883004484,69.4545429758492));
#682=CARTESIAN_POINT('',(-5.,10.5372900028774,69.887049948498));
#683=CARTESIAN_POINT('',(-5.,10.2982596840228,70.1026063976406));
#684=CARTESIAN_POINT('',(-5.,9.81867664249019,70.5320619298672));
#685=CARTESIAN_POINT('',(-5.,9.57812379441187,70.7459608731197));
#686=CARTESIAN_POINT('',(-5.,9.0951786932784,71.1716826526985));
#687=CARTESIAN_POINT('',(-5.,8.85278639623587,71.3835054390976));
#688=CARTESIAN_POINT('',(-5.,8.60931175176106,71.5940847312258));
#689=B_SPLINE_CURVE_WITH_KNOTS('',3,(#659,#660,#661,#662,#663,#664,#665,#666,#667,#668,#669,
#670,#671,#672,#673,#674,#675,#676,#677,#678,#679,#680,#681,#682,#683,#684,#685,#686,#687,#688),
.UNSPECIFIED.,.F.,.F.,(4,2,2,2,2,2,2,2,2,2,2,2,2,2,4),(0.,2.22106323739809,4.44212982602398,
6.66327269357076,8.88441424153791,11.1048004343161,13.3251849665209,15.5455618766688,
17.7659316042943,19.6968928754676,21.6278028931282,22.5934124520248,23.5590152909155,
24.5246987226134,25.4904053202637),.UNSPECIFIED.);
#690=CARTESIAN_POINT('',(-5.,15.0406947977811,65.7));
#691=VERTEX_POINT('',#690);
#692=EDGE_CURVE('E11',#691,#291,#689,.T.);
#693=ORIENTED_EDGE('',*,*,#692,.F.);
#694=CARTESIAN_POINT('',(0.,0.,65.7));
#695=DIRECTION('',(0.,0.,-1.));
#696=DIRECTION('',(-1.,0.,0.));
#697=AXIS2_PLACEMENT_3D('',#694,#695,#696);
#698=CIRCLE('',#697,15.85);
#699=CARTESIAN_POINT('',(5.,15.0406947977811,65.7));
#700=VERTEX_POINT('',#699);
#701=EDGE_CURVE('E347',#700,#691,#698,.F.);
#702=ORIENTED_EDGE('',*,*,#701,.F.);
#703=CARTESIAN_POINT('',(5.,8.60931175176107,71.5940847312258));
#704=CARTESIAN_POINT('',(5.,8.85278639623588,71.3835054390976));
#705=CARTESIAN_POINT('',(5.,9.09517869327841,71.1716826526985));
#706=CARTESIAN_POINT('',(5.,9.57812379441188,70.7459608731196));
#707=CARTESIAN_POINT('',(5.,9.8186766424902,70.5320619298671));
#708=CARTESIAN_POINT('',(5.,10.2982596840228,70.1026063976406));
#709=CARTESIAN_POINT('',(5.,10.5372900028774,69.887049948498));
#710=CARTESIAN_POINT('',(5.,11.0140883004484,69.4545429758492));
#711=CARTESIAN_POINT('',(5.,11.2518562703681,69.2375924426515));
#712=CARTESIAN_POINT('',(5.,11.9634949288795,68.5850772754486));
#713=CARTESIAN_POINT('',(5.,12.4357769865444,68.1477801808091));
#714=CARTESIAN_POINT('',(5.,13.3772594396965,67.2698635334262));
#715=CARTESIAN_POINT('',(5.,13.8464597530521,66.8292438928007));
#716=CARTESIAN_POINT('',(5.,14.852676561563,65.8793119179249));
#717=CARTESIAN_POINT('',(5.,15.3893173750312,65.3696018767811));
#718=CARTESIAN_POINT('',(5.,16.4603123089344,64.3477842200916));
#719=CARTESIAN_POINT('',(5.,16.9946664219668,63.8356765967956));
#720=CARTESIAN_POINT('',(5.,18.0616279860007,62.8096422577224));
#721=CARTESIAN_POINT('',(5.,18.594235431,62.2957155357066));
#722=CARTESIAN_POINT('',(5.,19.6580867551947,61.2664525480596));
#723=CARTESIAN_POINT('',(5.,20.1893306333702,60.7511162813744));
#724=CARTESIAN_POINT('',(5.,21.2509146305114,59.7191531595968));
#725=CARTESIAN_POINT('',(5.,21.7812543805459,59.2025259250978));
#726=CARTESIAN_POINT('',(5.,22.8410573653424,58.1683727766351));
#727=CARTESIAN_POINT('',(5.,23.3705205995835,57.6508468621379));
#728=CARTESIAN_POINT('',(5.,24.4287120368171,56.6150806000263));
#729=CARTESIAN_POINT('',(5.,24.9574402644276,56.0968402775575));
#730=CARTESIAN_POINT('',(5.,26.0142960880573,55.0597491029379));
#731=CARTESIAN_POINT('',(5.,26.5424236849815,54.5408982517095));
#732=CARTESIAN_POINT('',(5.,27.070309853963,54.0218021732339));
#733=B_SPLINE_CURVE_WITH_KNOTS('',3,(#703,#704,#705,#706,#707,#708,#709,#710,#711,#712,#713,
#714,#715,#716,#717,#718,#719,#720,#721,#722,#723,#724,#725,#726,#727,#728,#729,#730,#731,#732),
.UNSPECIFIED.,.F.,.F.,(4,2,2,2,2,2,2,2,2,2,2,2,2,2,4),(0.,0.96570659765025,1.93139002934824,
2.89699286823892,3.86260242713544,5.79351244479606,7.72447371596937,9.94484344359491,
12.1652203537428,14.3856048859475,16.6059910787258,18.8271326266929,21.0482754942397,
23.2693420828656,25.4904053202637),.UNSPECIFIED.);
#734=EDGE_CURVE('E43',#302,#700,#733,.T.);
#735=ORIENTED_EDGE('',*,*,#734,.F.);
#736=ORIENTED_EDGE('',*,*,#303,.F.);
#737=EDGE_LOOP('',(#693,#702,#735,#736));
#738=FACE_BOUND('',#737,.T.);
#739=ORIENTED_EDGE('',*,*,#578,.F.);
#740=EDGE_LOOP('',(#739));
#741=FACE_BOUND('',#740,.T.);
#742=ADVANCED_FACE('F32',(#738,#741),#658,.T.);
#743=CARTESIAN_POINT('',(-16.25,-16.25,31.5));
#744=DIRECTION('',(0.,0.,1.));
#745=DIRECTION('',(1.,0.,0.));
#746=AXIS2_PLACEMENT_3D('',#743,#744,#745);
#747=CYLINDRICAL_SURFACE('',#746,6.25);
#748=ORIENTED_EDGE('',*,*,#88,.T.);
#749=DIRECTION('',(0.,0.,1.));
#750=VECTOR('',#749,1.);
#751=CARTESIAN_POINT('',(-16.25,-22.5,31.5));
#752=LINE('',#751,#750);
#753=EDGE_CURVE('E288',#87,#226,#752,.T.);
#754=ORIENTED_EDGE('',*,*,#753,.T.);
#755=ORIENTED_EDGE('',*,*,#227,.F.);
#756=DIRECTION('',(0.,0.,1.));
#757=VECTOR('',#756,1.);
#758=CARTESIAN_POINT('',(-22.5,-16.25,31.5));
#759=LINE('',#758,#757);
#760=EDGE_CURVE('E287',#85,#217,#759,.T.);
#761=ORIENTED_EDGE('',*,*,#760,.F.);
#762=EDGE_LOOP('',(#748,#754,#755,#761));
#763=FACE_BOUND('',#762,.T.);
#764=ADVANCED_FACE('F400',(#763),#747,.T.);
#765=CARTESIAN_POINT('',(-22.5,16.25,31.5));
#766=DIRECTION('',(-1.,0.,0.));
#767=DIRECTION('',(0.,-1.,0.));
#768=AXIS2_PLACEMENT_3D('',#765,#766,#767);
#769=PLANE('',#768);
#770=ORIENTED_EDGE('',*,*,#96,.T.);
#771=ORIENTED_EDGE('',*,*,#760,.T.);
#772=ORIENTED_EDGE('',*,*,#218,.F.);
#773=DIRECTION('',(0.,0.,1.));
#774=VECTOR('',#773,1.);
#775=CARTESIAN_POINT('',(-22.5,16.25,31.5));
#776=LINE('',#775,#774);
#777=EDGE_CURVE('E302',#95,#215,#776,.T.);
#778=ORIENTED_EDGE('',*,*,#777,.F.);
#779=EDGE_LOOP('',(#770,#771,#772,#778));
#780=FACE_BOUND('',#779,.T.);
#781=ADVANCED_FACE('F395',(#780),#769,.T.);
#782=CARTESIAN_POINT('',(-16.25,16.25,31.5));
#783=DIRECTION('',(0.,0.,1.));
#784=DIRECTION('',(1.,0.,0.));
#785=AXIS2_PLACEMENT_3D('',#782,#783,#784);
#786=CYLINDRICAL_SURFACE('',#785,6.25);
#787=ORIENTED_EDGE('',*,*,#105,.T.);
#788=ORIENTED_EDGE('',*,*,#777,.T.);
#789=ORIENTED_EDGE('',*,*,#276,.F.);
#790=DIRECTION('',(0.,0.,1.));
#791=VECTOR('',#790,1.);
#792=CARTESIAN_POINT('',(-16.25,22.5,31.5));
#793=LINE('',#792,#791);
#794=EDGE_CURVE('E300',#104,#268,#793,.T.);
#795=ORIENTED_EDGE('',*,*,#794,.F.);
#796=EDGE_LOOP('',(#787,#788,#789,#795));
#797=FACE_BOUND('',#796,.T.);
#798=ADVANCED_FACE('F426',(#797),#786,.T.);
#799=CARTESIAN_POINT('',(-16.25,22.5,31.5));
#800=DIRECTION('',(0.,1.,0.));
#801=DIRECTION('',(0.,0.,1.));
#802=AXIS2_PLACEMENT_3D('',#799,#800,#801);
#803=PLANE('',#802);
#804=CARTESIAN_POINT('',(0.,22.5,52.5));
#805=DIRECTION('',(0.,1.,0.));
#806=DIRECTION('',(0.,0.,1.));
#807=AXIS2_PLACEMENT_3D('',#804,#805,#806);
#808=CIRCLE('',#807,5.025);
#809=CARTESIAN_POINT('',(0.,22.5,57.525));
#810=VERTEX_POINT('',#809);
#811=EDGE_CURVE('E331',#810,#810,#808,.T.);
#812=ORIENTED_EDGE('',*,*,#811,.F.);
#813=EDGE_LOOP('',(#812));
#814=FACE_BOUND('',#813,.T.);
#815=ORIENTED_EDGE('',*,*,#113,.T.);
#816=ORIENTED_EDGE('',*,*,#794,.T.);
#817=ORIENTED_EDGE('',*,*,#269,.F.);
#818=DIRECTION('',(0.,0.,1.));
#819=VECTOR('',#818,1.);
#820=CARTESIAN_POINT('',(16.25,22.5,31.5));
#821=LINE('',#820,#819);
#822=EDGE_CURVE('E298',#112,#260,#821,.T.);
#823=ORIENTED_EDGE('',*,*,#822,.F.);
#824=EDGE_LOOP('',(#815,#816,#817,#823));
#825=FACE_BOUND('',#824,.T.);
#826=ADVANCED_FACE('F421',(#814,#825),#803,.T.);
#827=CARTESIAN_POINT('',(16.25,16.25,31.5));
#828=DIRECTION('',(0.,0.,1.));
#829=DIRECTION('',(1.,0.,0.));
#830=AXIS2_PLACEMENT_3D('',#827,#828,#829);
#831=CYLINDRICAL_SURFACE('',#830,6.25);
#832=ORIENTED_EDGE('',*,*,#122,.T.);
#833=ORIENTED_EDGE('',*,*,#822,.T.);
#834=ORIENTED_EDGE('',*,*,#261,.F.);
#835=DIRECTION('',(0.,0.,1.));
#836=VECTOR('',#835,1.);
#837=CARTESIAN_POINT('',(22.5,16.25,31.5));
#838=LINE('',#837,#836);
#839=EDGE_CURVE('E296',#121,#251,#838,.T.);
#840=ORIENTED_EDGE('',*,*,#839,.F.);
#841=EDGE_LOOP('',(#832,#833,#834,#840));
#842=FACE_BOUND('',#841,.T.);
#843=ADVANCED_FACE('F417',(#842),#831,.T.);
#844=CARTESIAN_POINT('',(22.5,16.25,31.5));
#845=DIRECTION('',(1.,0.,0.));
#846=DIRECTION('',(0.,1.,0.));
#847=AXIS2_PLACEMENT_3D('',#844,#845,#846);
#848=PLANE('',#847);
#849=ORIENTED_EDGE('',*,*,#130,.T.);
#850=ORIENTED_EDGE('',*,*,#839,.T.);
#851=ORIENTED_EDGE('',*,*,#252,.F.);
#852=DIRECTION('',(0.,0.,1.));
#853=VECTOR('',#852,1.);
#854=CARTESIAN_POINT('',(22.5,-16.25,31.5));
#855=LINE('',#854,#853);
#856=EDGE_CURVE('E294',#129,#243,#855,.T.);
#857=ORIENTED_EDGE('',*,*,#856,.F.);
#858=EDGE_LOOP('',(#849,#850,#851,#857));
#859=FACE_BOUND('',#858,.T.);
#860=ADVANCED_FACE('F412',(#859),#848,.T.);
#861=CARTESIAN_POINT('',(16.25,-16.25,31.5));
#862=DIRECTION('',(0.,0.,1.));
#863=DIRECTION('',(1.,0.,0.));
#864=AXIS2_PLACEMENT_3D('',#861,#862,#863);
#865=CYLINDRICAL_SURFACE('',#864,6.25);
#866=ORIENTED_EDGE('',*,*,#139,.T.);
#867=ORIENTED_EDGE('',*,*,#856,.T.);
#868=ORIENTED_EDGE('',*,*,#244,.F.);
#869=DIRECTION('',(0.,0.,1.));
#870=VECTOR('',#869,1.);
#871=CARTESIAN_POINT('',(16.25,-22.5,31.5));
#872=LINE('',#871,#870);
#873=EDGE_CURVE('E290',#138,#234,#872,.T.);
#874=ORIENTED_EDGE('',*,*,#873,.F.);
#875=EDGE_LOOP('',(#866,#867,#868,#874));
#876=FACE_BOUND('',#875,.T.);
#877=ADVANCED_FACE('F407',(#876),#865,.T.);
#878=CARTESIAN_POINT('',(-16.25,-22.5,31.5));
#879=DIRECTION('',(0.,-1.,0.));
#880=DIRECTION('',(0.,0.,-1.));
#881=AXIS2_PLACEMENT_3D('',#878,#879,#880);
#882=PLANE('',#881);
#883=ORIENTED_EDGE('',*,*,#145,.T.);
#884=ORIENTED_EDGE('',*,*,#873,.T.);
#885=ORIENTED_EDGE('',*,*,#235,.F.);
#886=ORIENTED_EDGE('',*,*,#753,.F.);
#887=EDGE_LOOP('',(#883,#884,#885,#886));
#888=FACE_BOUND('',#887,.T.);
#889=ADVANCED_FACE('F196',(#888),#882,.T.);
#890=CARTESIAN_POINT('',(0.,22.5,52.5));
#891=DIRECTION('',(0.,1.,0.));
#892=DIRECTION('',(0.,0.,1.));
#893=AXIS2_PLACEMENT_3D('',#890,#891,#892);
#894=CYLINDRICAL_SURFACE('',#893,4.24999999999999);
#895=CARTESIAN_POINT('',(0.,11.9999318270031,56.75));
#896=CARTESIAN_POINT('',(-0.100444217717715,11.9995326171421,56.7500014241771));
#897=CARTESIAN_POINT('',(-0.200861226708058,11.9960986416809,56.7464341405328));
#898=CARTESIAN_POINT('',(-0.400843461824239,11.9832415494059,56.7322421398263));
#899=CARTESIAN_POINT('',(-0.500408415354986,11.9738165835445,56.7216152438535));
#900=CARTESIAN_POINT('',(-0.69792587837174,11.9491713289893,56.6934899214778));
#901=CARTESIAN_POINT('',(-0.795876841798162,11.9339457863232,56.6759852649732));
#902=CARTESIAN_POINT('',(-0.989374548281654,11.8980308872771,56.6344225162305));
#903=CARTESIAN_POINT('',(-1.08492017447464,11.877339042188,56.6103614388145));
#904=CARTESIAN_POINT('',(-1.36567981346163,11.8079800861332,56.5292812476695));
#905=CARTESIAN_POINT('',(-1.54651798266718,11.7518328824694,56.4631428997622));
#906=CARTESIAN_POINT('',(-1.89272829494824,11.6233786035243,56.309989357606));
#907=CARTESIAN_POINT('',(-2.05809687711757,11.5510678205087,56.222969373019));
#908=CARTESIAN_POINT('',(-2.32318880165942,11.4186134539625,56.0610935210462));
#909=CARTESIAN_POINT('',(-2.4273774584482,11.3616407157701,55.990821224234));
#910=CARTESIAN_POINT('',(-2.62751427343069,11.2431420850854,55.842777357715));
#911=CARTESIAN_POINT('',(-2.72346213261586,11.1816160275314,55.7650055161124));
#912=CARTESIAN_POINT('',(-2.90728046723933,11.0550740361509,55.6024694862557));
#913=CARTESIAN_POINT('',(-2.99512899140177,10.9900493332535,55.5176874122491));
#914=CARTESIAN_POINT('',(-3.16248351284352,10.8578899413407,55.341818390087));
#915=CARTESIAN_POINT('',(-3.24199061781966,10.7907555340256,55.2507322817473));
#916=CARTESIAN_POINT('',(-3.39422070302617,10.6543042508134,55.0606428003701));
#917=CARTESIAN_POINT('',(-3.46677630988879,10.5849705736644,54.9615175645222));
#918=CARTESIAN_POINT('',(-3.60327223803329,10.4469613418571,54.7570005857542));
#919=CARTESIAN_POINT('',(-3.66720961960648,10.3782860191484,54.6516067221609));
#920=CARTESIAN_POINT('',(-3.78616584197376,10.2436711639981,54.4346133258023));
#921=CARTESIAN_POINT('',(-3.84120435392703,10.1777258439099,54.3230282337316));
#922=CARTESIAN_POINT('',(-3.94212196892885,10.0509722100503,54.0930852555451));
#923=CARTESIAN_POINT('',(-3.98800879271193,9.99015959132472,53.9747331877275));
#924=CARTESIAN_POINT('',(-4.07213639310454,9.87404370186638,53.7241755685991));
#925=CARTESIAN_POINT('',(-4.10984130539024,9.8192049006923,53.5915680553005));
#926=CARTESIAN_POINT('',(-4.17283290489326,9.72465675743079,53.3182247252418));
#927=CARTESIAN_POINT('',(-4.19814640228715,9.6849147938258,53.177507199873));
#928=CARTESIAN_POINT('',(-4.22559170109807,9.64113449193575,52.9607716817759));
#929=CARTESIAN_POINT('',(-4.23300129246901,9.62915030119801,52.8869892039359));
#930=CARTESIAN_POINT('',(-4.24395964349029,9.61134246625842,52.7384173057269));
#931=CARTESIAN_POINT('',(-4.24751053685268,9.60551541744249,52.6636284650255));
#932=CARTESIAN_POINT('',(-4.2506380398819,9.60038659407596,52.5137715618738));
#933=CARTESIAN_POINT('',(-4.25021632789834,9.60108206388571,52.438703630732));
#934=CARTESIAN_POINT('',(-4.24542271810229,9.60893347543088,52.2890516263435));
#935=CARTESIAN_POINT('',(-4.24105083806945,9.61608938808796,52.2144675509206));
#936=CARTESIAN_POINT('',(-4.22406026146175,9.64362135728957,52.01443923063));
#937=CARTESIAN_POINT('',(-4.20780596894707,9.66975271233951,51.8900672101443));
#938=CARTESIAN_POINT('',(-4.16532671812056,9.73585024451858,51.6468370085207));
#939=CARTESIAN_POINT('',(-4.13908553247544,9.77583892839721,51.5279881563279));
#940=CARTESIAN_POINT('',(-4.08028174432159,9.86190476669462,51.3058872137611));
#941=CARTESIAN_POINT('',(-4.04840313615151,9.90722663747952,51.2021514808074));
#942=CARTESIAN_POINT('',(-3.9778268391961,10.0035381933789,50.9997004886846));
#943=CARTESIAN_POINT('',(-3.9391238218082,10.0545322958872,50.9009892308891));
#944=CARTESIAN_POINT('',(-3.8552312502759,10.1602886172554,50.7081363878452));
#945=CARTESIAN_POINT('',(-3.81002601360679,10.2150597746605,50.6140066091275));
#946=CARTESIAN_POINT('',(-3.71345266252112,10.3267143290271,50.4303305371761));
#947=CARTESIAN_POINT('',(-3.66208607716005,10.3835971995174,50.3407831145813));
#948=CARTESIAN_POINT('',(-3.54905525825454,10.5027583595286,50.1592719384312));
#949=CARTESIAN_POINT('',(-3.48690077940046,10.5651121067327,50.0676622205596));
#950=CARTESIAN_POINT('',(-3.35559328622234,10.6896831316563,49.8894938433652));
#951=CARTESIAN_POINT('',(-3.28643809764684,10.7519003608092,49.8029367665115));
#952=CARTESIAN_POINT('',(-3.06863215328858,10.9365740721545,49.5512362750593));
#953=CARTESIAN_POINT('',(-2.9094128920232,11.0573017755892,49.3936965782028));
#954=CARTESIAN_POINT('',(-2.57467589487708,11.2784628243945,49.1120742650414));
#955=CARTESIAN_POINT('',(-2.40101001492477,11.3797186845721,48.9864427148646));
#956=CARTESIAN_POINT('',(-2.02992084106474,11.5651570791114,48.7598098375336));
#957=CARTESIAN_POINT('',(-1.83252075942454,11.6493560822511,48.6587847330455));
#958=CARTESIAN_POINT('',(-1.45259496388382,11.7816950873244,48.5016040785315));
#959=CARTESIAN_POINT('',(-1.27333043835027,11.8335435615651,48.440723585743));
#960=CARTESIAN_POINT('',(-0.903947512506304,11.9175121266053,48.342862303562));
#961=CARTESIAN_POINT('',(-0.713837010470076,11.9496463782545,48.3058643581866));
#962=CARTESIAN_POINT('',(-0.327034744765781,11.9917236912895,48.2581065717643));
#963=CARTESIAN_POINT('',(-0.130318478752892,12.0015720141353,48.2474587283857));
#964=CARTESIAN_POINT('',(0.262476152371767,11.9979454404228,48.2535687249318));
#965=CARTESIAN_POINT('',(0.458554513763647,11.9844704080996,48.2703267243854));
#966=CARTESIAN_POINT('',(0.830669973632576,11.9371313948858,48.3280029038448));
#967=CARTESIAN_POINT('',(1.00716578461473,11.904707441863,48.3672110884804));
#968=CARTESIAN_POINT('',(1.35011809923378,11.823013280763,48.466197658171));
#969=CARTESIAN_POINT('',(1.51657311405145,11.7737405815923,48.5259790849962));
#970=CARTESIAN_POINT('',(1.85065721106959,11.6564190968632,48.6694074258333));
#971=CARTESIAN_POINT('',(2.01714081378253,11.5871142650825,48.754672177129));
#972=CARTESIAN_POINT('',(2.33349382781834,11.4359894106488,48.9431378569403));
#973=CARTESIAN_POINT('',(2.48334870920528,11.3541585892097,49.0463542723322));
#974=CARTESIAN_POINT('',(2.72988773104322,11.2037144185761,49.2399116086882));
#975=CARTESIAN_POINT('',(2.83042746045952,11.1370006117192,49.3268953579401));
#976=CARTESIAN_POINT('',(3.0218249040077,11.000286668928,49.5085979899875));
#977=CARTESIAN_POINT('',(3.11268213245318,10.9302863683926,49.6033172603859));
#978=CARTESIAN_POINT('',(3.28489061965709,10.7884512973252,49.8001603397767));
#979=CARTESIAN_POINT('',(3.36622283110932,10.7166131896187,49.9022983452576));
#980=CARTESIAN_POINT('',(3.51916686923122,10.5729833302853,50.1135860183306));
#981=CARTESIAN_POINT('',(3.59078214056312,10.5011915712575,50.2227331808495));
#982=CARTESIAN_POINT('',(3.70674780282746,10.3782290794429,50.4186852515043));
#983=CARTESIAN_POINT('',(3.75333156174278,10.3265738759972,50.5038717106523));
#984=CARTESIAN_POINT('',(3.84100957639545,10.2254812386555,50.678277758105));
#985=CARTESIAN_POINT('',(3.88210514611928,10.1760432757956,50.7674963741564));
#986=CARTESIAN_POINT('',(3.95850327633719,10.0807914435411,50.9499954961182));
#987=CARTESIAN_POINT('',(3.99381824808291,10.0349699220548,51.04326674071));
#988=CARTESIAN_POINT('',(4.05836787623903,9.94853471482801,51.2341795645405));
#989=CARTESIAN_POINT('',(4.0876057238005,9.90791830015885,51.3318188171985));
#990=CARTESIAN_POINT('',(4.1473180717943,9.82277525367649,51.5617645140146));
#991=CARTESIAN_POINT('',(4.17550756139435,9.78076190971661,51.6956473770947));
#992=CARTESIAN_POINT('',(4.21904577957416,9.71458777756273,51.9696336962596));
#993=CARTESIAN_POINT('',(4.23442647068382,9.69038256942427,52.1097207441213));
#994=CARTESIAN_POINT('',(4.2510811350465,9.66413205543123,52.3941330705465));
#995=CARTESIAN_POINT('',(4.2522356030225,9.66227448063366,52.5384840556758));
#996=CARTESIAN_POINT('',(4.23998670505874,9.68163442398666,52.8250547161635));
#997=CARTESIAN_POINT('',(4.22656490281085,9.70288116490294,52.9672714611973));
#998=CARTESIAN_POINT('',(4.18185160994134,9.7713384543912,53.2775615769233));
#999=CARTESIAN_POINT('',(4.14714745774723,9.82341422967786,53.4440157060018));
#1000=CARTESIAN_POINT('',(4.06065147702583,9.94585804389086,53.7655176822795));
#1001=CARTESIAN_POINT('',(4.00880088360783,10.0162888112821,53.9205240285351));
#1002=CARTESIAN_POINT('',(3.9012360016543,10.153013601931,54.1911070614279));
#1003=CARTESIAN_POINT('',(3.84808577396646,10.2175911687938,54.3086138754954));
#1004=CARTESIAN_POINT('',(3.7323546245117,10.3504569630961,54.5367630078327));
#1005=CARTESIAN_POINT('',(3.66976830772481,10.4187472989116,54.6474013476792));
#1006=CARTESIAN_POINT('',(3.53535771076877,10.5568177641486,54.8621617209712));
#1007=CARTESIAN_POINT('',(3.46352187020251,10.6265996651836,54.9662753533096));
#1008=CARTESIAN_POINT('',(3.31075537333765,10.7657681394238,55.1678426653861));
#1009=CARTESIAN_POINT('',(3.22982664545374,10.8351547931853,55.2652977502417));
#1010=CARTESIAN_POINT('',(3.05589588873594,10.9743664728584,55.4565648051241));
#1011=CARTESIAN_POINT('',(2.96257419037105,11.0441243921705,55.5501359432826));
#1012=CARTESIAN_POINT('',(2.76612125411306,11.1800159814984,55.7293583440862));
#1013=CARTESIAN_POINT('',(2.66298806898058,11.2461489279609,55.8150080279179));
#1014=CARTESIAN_POINT('',(2.44725167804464,11.3730452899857,55.9773001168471));
#1015=CARTESIAN_POINT('',(2.3346734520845,11.4338220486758,56.0539650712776));
#1016=CARTESIAN_POINT('',(2.10021887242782,11.5485427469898,56.1973610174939));
#1017=CARTESIAN_POINT('',(1.97834812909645,11.6024907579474,56.2640979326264));
#1018=CARTESIAN_POINT('',(1.68249145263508,11.7189738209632,56.4073094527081));
#1019=CARTESIAN_POINT('',(1.5049166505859,11.7781537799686,56.4793315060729));
#1020=CARTESIAN_POINT('',(1.2291816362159,11.8524798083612,56.5695196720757));
#1021=CARTESIAN_POINT('',(1.13575539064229,11.8748404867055,56.5965994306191));
#1022=CARTESIAN_POINT('',(0.946235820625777,11.9143721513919,56.6444752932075));
#1023=CARTESIAN_POINT('',(0.850143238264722,11.9315445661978,56.6652731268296));
#1024=CARTESIAN_POINT('',(0.629754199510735,11.9642085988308,56.7049482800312));
#1025=CARTESIAN_POINT('',(0.504831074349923,11.978002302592,56.7218002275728));
#1026=CARTESIAN_POINT('',(0.253257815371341,11.9961165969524,56.7443264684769));
#1027=CARTESIAN_POINT('',(0.12660729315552,12.0004350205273,56.7499982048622));
#1028=CARTESIAN_POINT('',(0.,11.9999318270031,56.75));
#1029=B_SPLINE_CURVE_WITH_KNOTS('',3,(#895,#896,#897,#898,#899,#900,#901,#902,#903,#904,#905,
#906,#907,#908,#909,#910,#911,#912,#913,#914,#915,#916,#917,#918,#919,#920,#921,#922,#923,#924,
#925,#926,#927,#928,#929,#930,#931,#932,#933,#934,#935,#936,#937,#938,#939,#940,#941,#942,#943,
#944,#945,#946,#947,#948,#949,#950,#951,#952,#953,#954,#955,#956,#957,#958,#959,#960,#961,#962,
#963,#964,#965,#966,#967,#968,#969,#970,#971,#972,#973,#974,#975,#976,#977,#978,#979,#980,#981,
#982,#983,#984,#985,#986,#987,#988,#989,#990,#991,#992,#993,#994,#995,#996,#997,#998,#999,#1000,
#1001,#1002,#1003,#1004,#1005,#1006,#1007,#1008,#1009,#1010,#1011,#1012,#1013,#1014,#1015,#1016,
#1017,#1018,#1019,#1020,#1021,#1022,#1023,#1024,#1025,#1026,#1027,#1028),.UNSPECIFIED.,.T.,.F.,
(4,2,2,2,2,2,2,2,2,2,2,2,2,2,2,2,2,2,2,2,2,2,2,2,2,2,2,2,2,2,2,2,2,2,2,2,2,2,2,2,2,2,2,2,2,2,2,
2,2,2,2,2,2,2,2,2,2,2,2,2,2,2,2,2,2,2,4),(0.,0.301200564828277,0.602494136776,0.904061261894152,
1.20576592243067,1.80464492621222,2.40366144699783,2.8171000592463,3.23055366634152,
3.64509678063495,4.05958477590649,4.48235787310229,4.90527481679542,5.32724371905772,
5.74885511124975,6.19287010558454,6.63592013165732,6.86095929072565,7.08587394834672,
7.31069358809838,7.53551221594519,7.9182400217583,8.30159238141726,8.65390077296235,
9.00648548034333,9.35993529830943,9.7132975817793,10.0941517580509,10.4751245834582,
11.2355857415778,11.944188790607,12.6521043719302,13.2385299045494,13.8245337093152,
14.4130240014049,15.0015177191,15.5502250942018,16.0990136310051,16.695303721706,
17.292110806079,17.7378060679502,18.1835236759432,18.6301178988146,19.0765533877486,
19.4062817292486,19.7359309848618,20.0648629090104,20.3936216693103,20.8215027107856,
21.2483128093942,21.6787058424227,22.1096438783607,22.6401642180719,23.1725219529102,
23.6046807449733,24.0370875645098,24.470040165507,24.9029011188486,25.3506601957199,
25.798508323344,26.2452072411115,26.6916385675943,27.2904634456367,27.5895859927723,
27.888626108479,28.2681946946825,28.6478500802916),.UNSPECIFIED.);
#1030=EDGE_CURVE('E164',#368,#368,#1029,.T.);
#1031=ORIENTED_EDGE('',*,*,#1030,.T.);
#1032=EDGE_LOOP('',(#1031));
#1033=FACE_BOUND('',#1032,.T.);
#1034=CARTESIAN_POINT('',(0.,21.3931852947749,52.5));
#1035=DIRECTION('',(0.,1.,0.));
#1036=DIRECTION('',(0.,0.,1.));
#1037=AXIS2_PLACEMENT_3D('',#1034,#1035,#1036);
#1038=CIRCLE('',#1037,4.25);
#1039=CARTESIAN_POINT('',(0.,21.3931852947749,56.75));
#1040=VERTEX_POINT('',#1039);
#1041=EDGE_CURVE('E328',#1040,#1040,#1038,.T.);
#1042=ORIENTED_EDGE('',*,*,#1041,.T.);
#1043=EDGE_LOOP('',(#1042));
#1044=FACE_BOUND('',#1043,.T.);
#1045=ADVANCED_FACE('F179',(#1033,#1044),#894,.F.);
#1046=CARTESIAN_POINT('',(0.,22.5,52.5));
#1047=DIRECTION('',(0.,1.,0.));
#1048=DIRECTION('',(0.,0.,1.));
#1049=AXIS2_PLACEMENT_3D('',#1046,#1047,#1048);
#1050=CONICAL_SURFACE('',#1049,5.025,0.610865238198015);
#1051=ORIENTED_EDGE('',*,*,#1041,.F.);
#1052=EDGE_LOOP('',(#1051));
#1053=FACE_BOUND('',#1052,.T.);
#1054=ORIENTED_EDGE('',*,*,#811,.T.);
#1055=EDGE_LOOP('',(#1054));
#1056=FACE_BOUND('',#1055,.T.);
#1057=ADVANCED_FACE('F189',(#1053,#1056),#1050,.F.);
#1058=CARTESIAN_POINT('',(0.0199417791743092,6.99997159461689,46.5));
#1059=DIRECTION('',(0.,0.,-1.));
#1060=DIRECTION('',(-1.,0.,0.));
#1061=AXIS2_PLACEMENT_3D('',#1058,#1059,#1060);
#1062=PLANE('',#1061);
#1063=CARTESIAN_POINT('',(0.0199417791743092,6.99997159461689,46.5));
#1064=DIRECTION('',(0.,0.,1.));
#1065=DIRECTION('',(-1.,0.,0.));
#1066=AXIS2_PLACEMENT_3D('',#1063,#1064,#1065);
#1067=CIRCLE('',#1066,5.);
#1068=EDGE_CURVE('E57',#351,#360,#1067,.T.);
#1069=ORIENTED_EDGE('',*,*,#1068,.T.);
#1070=ORIENTED_EDGE('',*,*,#361,.F.);
#1071=EDGE_LOOP('',(#1069,#1070));
#1072=FACE_BOUND('',#1071,.T.);
#1073=ADVANCED_FACE('F187',(#1072),#1062,.F.);
#1074=CARTESIAN_POINT('',(0.0199417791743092,6.99997159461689,46.5));
#1075=DIRECTION('',(0.,0.,1.));
#1076=DIRECTION('',(1.,0.,0.));
#1077=AXIS2_PLACEMENT_3D('',#1074,#1075,#1076);
#1078=CYLINDRICAL_SURFACE('',#1077,5.);
#1079=ORIENTED_EDGE('',*,*,#352,.T.);
#1080=CARTESIAN_POINT('',(0.0199417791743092,6.99997159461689,65.7));
#1081=DIRECTION('',(0.,0.,-1.));
#1082=DIRECTION('',(-1.,0.,0.));
#1083=AXIS2_PLACEMENT_3D('',#1080,#1081,#1082);
#1084=CIRCLE('',#1083,5.);
#1085=EDGE_CURVE('E696',#343,#372,#1084,.F.);
#1086=ORIENTED_EDGE('',*,*,#1085,.T.);
#1087=ORIENTED_EDGE('',*,*,#373,.F.);
#1088=ORIENTED_EDGE('',*,*,#1030,.F.);
#1089=ORIENTED_EDGE('',*,*,#369,.F.);
#1090=ORIENTED_EDGE('',*,*,#1068,.F.);
#1091=EDGE_LOOP('',(#1079,#1086,#1087,#1088,#1089,#1090));
#1092=FACE_BOUND('',#1091,.T.);
#1093=ADVANCED_FACE('F183',(#1092),#1078,.F.);
#1094=CARTESIAN_POINT('',(-5.,0.,65.7));
#1095=DIRECTION('',(-1.,0.,0.));
#1096=DIRECTION('',(0.,0.,1.));
#1097=AXIS2_PLACEMENT_3D('',#1094,#1095,#1096);
#1098=PLANE('',#1097);
#1099=DIRECTION('',(0.,-1.,0.));
#1100=VECTOR('',#1099,1.);
#1101=CARTESIAN_POINT('',(-5.,0.,65.7));
#1102=LINE('',#1101,#1100);
#1103=EDGE_CURVE('E143',#691,#376,#1102,.T.);
#1104=ORIENTED_EDGE('',*,*,#1103,.F.);
#1105=ORIENTED_EDGE('',*,*,#692,.T.);
#1106=ORIENTED_EDGE('',*,*,#294,.T.);
#1107=ORIENTED_EDGE('',*,*,#383,.F.);
#1108=EDGE_LOOP('',(#1104,#1105,#1106,#1107));
#1109=FACE_BOUND('',#1108,.T.);
#1110=ADVANCED_FACE('F140',(#1109),#1098,.F.);
#1111=CARTESIAN_POINT('',(5.,0.,65.7));
#1112=DIRECTION('',(1.,0.,0.));
#1113=DIRECTION('',(0.,0.,-1.));
#1114=AXIS2_PLACEMENT_3D('',#1111,#1112,#1113);
#1115=PLANE('',#1114);
#1116=ORIENTED_EDGE('',*,*,#311,.T.);
#1117=ORIENTED_EDGE('',*,*,#734,.T.);
#1118=DIRECTION('',(0.,1.,0.));
#1119=VECTOR('',#1118,1.);
#1120=CARTESIAN_POINT('',(5.,0.,65.7));
#1121=LINE('',#1120,#1119);
#1122=EDGE_CURVE('E351',#334,#700,#1121,.T.);
#1123=ORIENTED_EDGE('',*,*,#1122,.F.);
#1124=ORIENTED_EDGE('',*,*,#335,.F.);
#1125=EDGE_LOOP('',(#1116,#1117,#1123,#1124));
#1126=FACE_BOUND('',#1125,.T.);
#1127=ADVANCED_FACE('F624',(#1126),#1115,.F.);
#1128=CARTESIAN_POINT('',(-5.,22.5,65.7));
#1129=DIRECTION('',(0.,0.,-1.));
#1130=DIRECTION('',(-1.,0.,0.));
#1131=AXIS2_PLACEMENT_3D('',#1128,#1129,#1130);
#1132=PLANE('',#1131);
#1133=ORIENTED_EDGE('',*,*,#701,.T.);
#1134=ORIENTED_EDGE('',*,*,#1103,.T.);
#1135=ORIENTED_EDGE('',*,*,#377,.F.);
#1136=ORIENTED_EDGE('',*,*,#1085,.F.);
#1137=ORIENTED_EDGE('',*,*,#344,.F.);
#1138=ORIENTED_EDGE('',*,*,#1122,.T.);
#1139=EDGE_LOOP('',(#1133,#1134,#1135,#1136,#1137,#1138));
#1140=FACE_BOUND('',#1139,.T.);
#1141=ADVANCED_FACE('F632',(#1140),#1132,.F.);
#1142=CARTESIAN_POINT('',(-16.2634559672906,-16.2634559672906,60.));
#1143=DIRECTION('',(0.,0.,1.));
#1144=DIRECTION('',(1.,0.,0.));
#1145=AXIS2_PLACEMENT_3D('',#1142,#1143,#1144);
#1146=CYLINDRICAL_SURFACE('',#1145,2.74999999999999);
#1147=ORIENTED_EDGE('',*,*,#195,.T.);
#1148=EDGE_LOOP('',(#1147));
#1149=FACE_BOUND('',#1148,.T.);
#1150=ORIENTED_EDGE('',*,*,#64,.F.);
#1151=EDGE_LOOP('',(#1150));
#1152=FACE_BOUND('',#1151,.T.);
#1153=ADVANCED_FACE('F641',(#1149,#1152),#1146,.F.);
#1154=CARTESIAN_POINT('',(16.2634559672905,-16.2634559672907,60.));
#1155=DIRECTION('',(0.,0.,1.));
#1156=DIRECTION('',(1.,0.,0.));
#1157=AXIS2_PLACEMENT_3D('',#1154,#1155,#1156);
#1158=CYLINDRICAL_SURFACE('',#1157,2.74999999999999);
#1159=ORIENTED_EDGE('',*,*,#184,.T.);
#1160=EDGE_LOOP('',(#1159));
#1161=FACE_BOUND('',#1160,.T.);
#1162=ORIENTED_EDGE('',*,*,#53,.F.);
#1163=EDGE_LOOP('',(#1162));
#1164=FACE_BOUND('',#1163,.T.);
#1165=ADVANCED_FACE('F659',(#1161,#1164),#1158,.F.);
#1166=CARTESIAN_POINT('',(16.2634559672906,16.2634559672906,60.));
#1167=DIRECTION('',(0.,0.,1.));
#1168=DIRECTION('',(1.,0.,0.));
#1169=AXIS2_PLACEMENT_3D('',#1166,#1167,#1168);
#1170=CYLINDRICAL_SURFACE('',#1169,2.74999999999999);
#1171=ORIENTED_EDGE('',*,*,#173,.T.);
#1172=EDGE_LOOP('',(#1171));
#1173=FACE_BOUND('',#1172,.T.);
#1174=ORIENTED_EDGE('',*,*,#42,.F.);
#1175=EDGE_LOOP('',(#1174));
#1176=FACE_BOUND('',#1175,.T.);
#1177=ADVANCED_FACE('F669',(#1173,#1176),#1170,.F.);
#1178=CARTESIAN_POINT('',(-16.2634559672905,16.2634559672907,60.));
#1179=DIRECTION('',(0.,0.,1.));
#1180=DIRECTION('',(1.,0.,0.));
#1181=AXIS2_PLACEMENT_3D('',#1178,#1179,#1180);
#1182=CYLINDRICAL_SURFACE('',#1181,2.74999999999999);
#1183=ORIENTED_EDGE('',*,*,#162,.T.);
#1184=EDGE_LOOP('',(#1183));
#1185=FACE_BOUND('',#1184,.T.);
#1186=ORIENTED_EDGE('',*,*,#31,.F.);
#1187=EDGE_LOOP('',(#1186));
#1188=FACE_BOUND('',#1187,.T.);
#1189=ADVANCED_FACE('F379',(#1185,#1188),#1182,.F.);
#1190=CLOSED_SHELL('',(#149,#280,#322,#398,#418,#438,#458,#478,#493,#521,#541,#553,#565,#653,
#742,#764,#781,#798,#826,#843,#860,#877,#889,#1045,#1057,#1073,#1093,#1110,#1127,#1141,#1153,
#1165,#1177,#1189));
#1191=MANIFOLD_SOLID_BREP('B2',#1190);
#1192=ADVANCED_BREP_SHAPE_REPRESENTATION('',(#18,#1191),#14);
#1193=SHAPE_DEFINITION_REPRESENTATION(#9,#1192);
ENDSEC;
END-ISO-10303-21;
